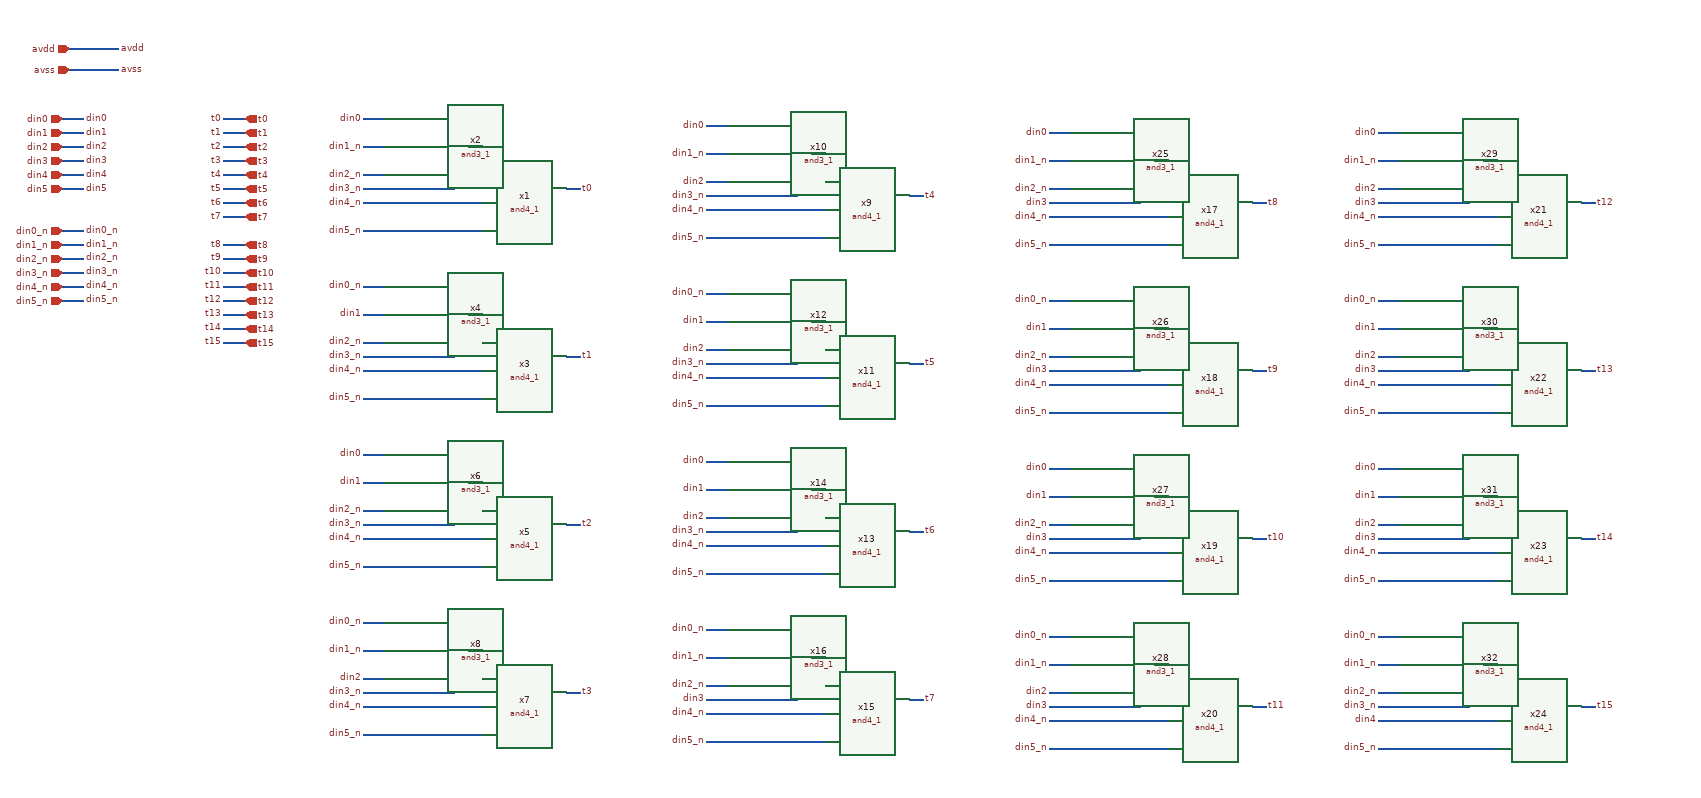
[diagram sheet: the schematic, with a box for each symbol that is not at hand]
v {xschem version=3.4.5 file_version=1.2
}
G {}
K {}
V {}
S {}
E {}
N -50 -70 -20 -70 {
lab=din0}
N -50 -50 -20 -50 {
lab=din1}
N -50 -30 -20 -30 {
lab=din2}
N -50 -10 -20 -10 {
lab=din3}
N -50 10 -20 10 {
lab=din4}
N -50 30 -20 30 {
lab=din5}
N -50 90 -20 90 {
lab=din0_n}
N -50 110 -20 110 {
lab=din1_n}
N -50 130 -20 130 {
lab=din2_n}
N -50 150 -20 150 {
lab=din3_n}
N -50 170 -20 170 {
lab=din4_n}
N -50 190 -20 190 {
lab=din5_n}
N 180 -70 210 -70 {
lab=t0}
N 180 -50 210 -50 {
lab=t1}
N 180 -30 210 -30 {
lab=t2}
N 180 -10 210 -10 {
lab=t3}
N 180 10 210 10 {
lab=t4}
N 180 30 210 30 {
lab=t5}
N 180 50 210 50 {
lab=t6}
N 180 70 210 70 {
lab=t7}
N 180 110 210 110 {
lab=t8}
N 180 130 210 130 {
lab=t9}
N 180 150 210 150 {
lab=t10}
N 180 170 210 170 {
lab=t11}
N 180 190 210 190 {
lab=t12}
N 180 210 210 210 {
lab=t13}
N 180 230 210 230 {
lab=t14}
N 180 250 210 250 {
lab=t15}
N 530 -30 550 -30 {
lab=#net1}
N 380 -70 410 -70 {
lab=din0_n}
N 380 -30 410 -30 {
lab=din1_n}
N 380 10 410 10 {
lab=din2_n}
N 510 10 550 10 {
lab=din3_n}
N 510 10 510 30 {
lab=din3_n}
N 380 30 510 30 {
lab=din3_n}
N 380 50 550 50 {
lab=din4_n}
N 380 90 550 90 {
lab=din5_n}
N 670 30 690 30 {
lab=t0}
N 530 210 550 210 {
lab=#net1}
N 380 170 410 170 {
lab=din0_n}
N 380 210 410 210 {
lab=din1_n}
N 380 250 410 250 {
lab=din2_n}
N 510 250 550 250 {
lab=din3_n}
N 510 250 510 270 {
lab=din3_n}
N 380 270 510 270 {
lab=din3_n}
N 380 290 550 290 {
lab=din4_n}
N 380 330 550 330 {
lab=din5_n}
N 670 270 690 270 {
lab=t0}
N 530 450 550 450 {
lab=#net1}
N 380 410 410 410 {
lab=din0_n}
N 380 450 410 450 {
lab=din1_n}
N 380 490 410 490 {
lab=din2_n}
N 510 490 550 490 {
lab=din3_n}
N 510 490 510 510 {
lab=din3_n}
N 380 510 510 510 {
lab=din3_n}
N 380 530 550 530 {
lab=din4_n}
N 380 570 550 570 {
lab=din5_n}
N 670 510 690 510 {
lab=t0}
N 530 690 550 690 {
lab=#net1}
N 380 650 410 650 {
lab=din0_n}
N 380 690 410 690 {
lab=din1_n}
N 380 730 410 730 {
lab=din2_n}
N 510 730 550 730 {
lab=din3_n}
N 510 730 510 750 {
lab=din3_n}
N 380 750 510 750 {
lab=din3_n}
N 380 770 550 770 {
lab=din4_n}
N 380 810 550 810 {
lab=din5_n}
N 670 750 690 750 {
lab=t0}
N 1020 -20 1040 -20 {
lab=#net1}
N 870 -60 900 -60 {
lab=din0_n}
N 870 -20 900 -20 {
lab=din1_n}
N 870 20 900 20 {
lab=din2_n}
N 1000 20 1040 20 {
lab=din3_n}
N 1000 20 1000 40 {
lab=din3_n}
N 870 40 1000 40 {
lab=din3_n}
N 870 60 1040 60 {
lab=din4_n}
N 870 100 1040 100 {
lab=din5_n}
N 1160 40 1180 40 {
lab=t0}
N 1020 220 1040 220 {
lab=#net1}
N 870 180 900 180 {
lab=din0_n}
N 870 220 900 220 {
lab=din1_n}
N 870 260 900 260 {
lab=din2_n}
N 1000 260 1040 260 {
lab=din3_n}
N 1000 260 1000 280 {
lab=din3_n}
N 870 280 1000 280 {
lab=din3_n}
N 870 300 1040 300 {
lab=din4_n}
N 870 340 1040 340 {
lab=din5_n}
N 1160 280 1180 280 {
lab=t0}
N 1020 460 1040 460 {
lab=#net1}
N 870 420 900 420 {
lab=din0_n}
N 870 460 900 460 {
lab=din1_n}
N 870 500 900 500 {
lab=din2_n}
N 1000 500 1040 500 {
lab=din3_n}
N 1000 500 1000 520 {
lab=din3_n}
N 870 520 1000 520 {
lab=din3_n}
N 870 540 1040 540 {
lab=din4_n}
N 870 580 1040 580 {
lab=din5_n}
N 1160 520 1180 520 {
lab=t0}
N 1020 700 1040 700 {
lab=#net1}
N 870 660 900 660 {
lab=din0_n}
N 870 700 900 700 {
lab=din1_n}
N 870 740 900 740 {
lab=din2_n}
N 1000 740 1040 740 {
lab=din3_n}
N 1000 740 1000 760 {
lab=din3_n}
N 870 760 1000 760 {
lab=din3_n}
N 870 780 1040 780 {
lab=din4_n}
N 870 820 1040 820 {
lab=din5_n}
N 1160 760 1180 760 {
lab=t0}
N 1510 -10 1530 -10 {
lab=#net1}
N 1360 -50 1390 -50 {
lab=din0_n}
N 1360 -10 1390 -10 {
lab=din1_n}
N 1360 30 1390 30 {
lab=din2_n}
N 1490 30 1530 30 {
lab=din3_n}
N 1490 30 1490 50 {
lab=din3_n}
N 1360 50 1490 50 {
lab=din3_n}
N 1360 70 1530 70 {
lab=din4_n}
N 1360 110 1530 110 {
lab=din5_n}
N 1650 50 1670 50 {
lab=t0}
N 1510 230 1530 230 {
lab=#net1}
N 1360 190 1390 190 {
lab=din0_n}
N 1360 230 1390 230 {
lab=din1_n}
N 1360 270 1390 270 {
lab=din2_n}
N 1490 270 1530 270 {
lab=din3_n}
N 1490 270 1490 290 {
lab=din3_n}
N 1360 290 1490 290 {
lab=din3_n}
N 1360 310 1530 310 {
lab=din4_n}
N 1360 350 1530 350 {
lab=din5_n}
N 1650 290 1670 290 {
lab=t0}
N 1510 470 1530 470 {
lab=#net1}
N 1360 430 1390 430 {
lab=din0_n}
N 1360 470 1390 470 {
lab=din1_n}
N 1360 510 1390 510 {
lab=din2_n}
N 1490 510 1530 510 {
lab=din3_n}
N 1490 510 1490 530 {
lab=din3_n}
N 1360 530 1490 530 {
lab=din3_n}
N 1360 550 1530 550 {
lab=din4_n}
N 1360 590 1530 590 {
lab=din5_n}
N 1650 530 1670 530 {
lab=t0}
N 1510 710 1530 710 {
lab=#net1}
N 1360 670 1390 670 {
lab=din0_n}
N 1360 710 1390 710 {
lab=din1_n}
N 1360 750 1390 750 {
lab=din2_n}
N 1490 750 1530 750 {
lab=din3_n}
N 1490 750 1490 770 {
lab=din3_n}
N 1360 770 1490 770 {
lab=din3_n}
N 1360 790 1530 790 {
lab=din4_n}
N 1360 830 1530 830 {
lab=din5_n}
N 1650 770 1670 770 {
lab=t0}
N 1980 -10 2000 -10 {
lab=#net1}
N 1830 -50 1860 -50 {
lab=din0_n}
N 1830 -10 1860 -10 {
lab=din1_n}
N 1830 30 1860 30 {
lab=din2_n}
N 1960 30 2000 30 {
lab=din3_n}
N 1960 30 1960 50 {
lab=din3_n}
N 1830 50 1960 50 {
lab=din3_n}
N 1830 70 2000 70 {
lab=din4_n}
N 1830 110 2000 110 {
lab=din5_n}
N 2120 50 2140 50 {
lab=t0}
N 1980 230 2000 230 {
lab=#net1}
N 1830 190 1860 190 {
lab=din0_n}
N 1830 230 1860 230 {
lab=din1_n}
N 1830 270 1860 270 {
lab=din2_n}
N 1960 270 2000 270 {
lab=din3_n}
N 1960 270 1960 290 {
lab=din3_n}
N 1830 290 1960 290 {
lab=din3_n}
N 1830 310 2000 310 {
lab=din4_n}
N 1830 350 2000 350 {
lab=din5_n}
N 2120 290 2140 290 {
lab=t0}
N 1980 470 2000 470 {
lab=#net1}
N 1830 430 1860 430 {
lab=din0_n}
N 1830 470 1860 470 {
lab=din1_n}
N 1830 510 1860 510 {
lab=din2_n}
N 1960 510 2000 510 {
lab=din3_n}
N 1960 510 1960 530 {
lab=din3_n}
N 1830 530 1960 530 {
lab=din3_n}
N 1830 550 2000 550 {
lab=din4_n}
N 1830 590 2000 590 {
lab=din5_n}
N 2120 530 2140 530 {
lab=t0}
N 1980 710 2000 710 {
lab=#net1}
N 1830 670 1860 670 {
lab=din0_n}
N 1830 710 1860 710 {
lab=din1_n}
N 1830 750 1860 750 {
lab=din2_n}
N 1960 750 2000 750 {
lab=din3_n}
N 1960 750 1960 770 {
lab=din3_n}
N 1830 770 1960 770 {
lab=din3_n}
N 1830 790 2000 790 {
lab=din4_n}
N 1830 830 2000 830 {
lab=din5_n}
N 2120 770 2140 770 {
lab=t0}
N -40 -170 30 -170 {}
N -40 -140 30 -140 {}
C {devices/ipin.sym} -50 -70 0 0 {name=p1 lab=din0}
C {devices/ipin.sym} -50 -50 0 0 {name=p2 lab=din1}
C {devices/ipin.sym} -50 -30 0 0 {name=p3 lab=din2}
C {devices/ipin.sym} -50 -10 0 0 {name=p4 lab=din3}
C {devices/ipin.sym} -50 10 0 0 {name=p5 lab=din4}
C {devices/ipin.sym} -50 30 0 0 {name=p6 lab=din5}
C {devices/ipin.sym} -50 90 0 0 {name=p7 lab=din0_n}
C {devices/ipin.sym} -50 110 0 0 {name=p8 lab=din1_n}
C {devices/ipin.sym} -50 130 0 0 {name=p9 lab=din2_n}
C {devices/ipin.sym} -50 150 0 0 {name=p10 lab=din3_n}
C {devices/ipin.sym} -50 170 0 0 {name=p11 lab=din4_n}
C {devices/ipin.sym} -50 190 0 0 {name=p12 lab=din5_n}
C {devices/opin.sym} 210 -70 0 0 {name=p13 lab=t0}
C {devices/opin.sym} 210 -50 0 0 {name=p14 lab=t1}
C {devices/opin.sym} 210 -30 0 0 {name=p15 lab=t2}
C {devices/opin.sym} 210 -10 0 0 {name=p16 lab=t3}
C {devices/opin.sym} 210 10 0 0 {name=p17 lab=t4}
C {devices/opin.sym} 210 30 0 0 {name=p18 lab=t5}
C {devices/opin.sym} 210 50 0 0 {name=p19 lab=t6}
C {devices/opin.sym} 210 70 0 0 {name=p20 lab=t7}
C {devices/lab_pin.sym} 180 -70 0 0 {name=p21 sig_type=std_logic lab=t0}
C {devices/lab_pin.sym} 180 -50 0 0 {name=p22 sig_type=std_logic lab=t1}
C {devices/lab_pin.sym} 180 -30 0 0 {name=p23 sig_type=std_logic lab=t2}
C {devices/lab_pin.sym} 180 -10 0 0 {name=p24 sig_type=std_logic lab=t3}
C {devices/lab_pin.sym} 180 10 0 0 {name=p25 sig_type=std_logic lab=t4}
C {devices/lab_pin.sym} 180 30 0 0 {name=p26 sig_type=std_logic lab=t5}
C {devices/lab_pin.sym} 180 50 0 0 {name=p27 sig_type=std_logic lab=t6}
C {devices/lab_pin.sym} 180 70 0 0 {name=p28 sig_type=std_logic lab=t7}
C {devices/lab_pin.sym} -20 -70 0 1 {name=p29 sig_type=std_logic lab=din0}
C {devices/lab_pin.sym} -20 -50 0 1 {name=p30 sig_type=std_logic lab=din1}
C {devices/lab_pin.sym} -20 -30 0 1 {name=p31 sig_type=std_logic lab=din2}
C {devices/lab_pin.sym} -20 -10 0 1 {name=p32 sig_type=std_logic lab=din3}
C {devices/lab_pin.sym} -20 10 0 1 {name=p33 sig_type=std_logic lab=din4}
C {devices/lab_pin.sym} -20 30 0 1 {name=p34 sig_type=std_logic lab=din5}
C {devices/lab_pin.sym} -20 90 0 1 {name=p35 sig_type=std_logic lab=din0_n}
C {devices/lab_pin.sym} -20 110 0 1 {name=p36 sig_type=std_logic lab=din1_n}
C {devices/lab_pin.sym} -20 130 0 1 {name=p37 sig_type=std_logic lab=din2_n}
C {devices/lab_pin.sym} -20 150 0 1 {name=p38 sig_type=std_logic lab=din3_n}
C {devices/lab_pin.sym} -20 170 0 1 {name=p39 sig_type=std_logic lab=din4_n}
C {devices/lab_pin.sym} -20 190 0 1 {name=p40 sig_type=std_logic lab=din5_n}
C {devices/opin.sym} 210 110 0 0 {name=p41 lab=t8}
C {devices/opin.sym} 210 130 0 0 {name=p42 lab=t9}
C {devices/opin.sym} 210 150 0 0 {name=p43 lab=t10}
C {devices/opin.sym} 210 170 0 0 {name=p44 lab=t11}
C {devices/opin.sym} 210 190 0 0 {name=p45 lab=t12}
C {devices/opin.sym} 210 210 0 0 {name=p46 lab=t13}
C {devices/opin.sym} 210 230 0 0 {name=p47 lab=t14}
C {devices/opin.sym} 210 250 0 0 {name=p48 lab=t15}
C {devices/lab_pin.sym} 180 110 0 0 {name=p49 sig_type=std_logic lab=t8}
C {devices/lab_pin.sym} 180 130 0 0 {name=p50 sig_type=std_logic lab=t9}
C {devices/lab_pin.sym} 180 150 0 0 {name=p51 sig_type=std_logic lab=t10}
C {devices/lab_pin.sym} 180 170 0 0 {name=p52 sig_type=std_logic lab=t11}
C {devices/lab_pin.sym} 180 190 0 0 {name=p53 sig_type=std_logic lab=t12}
C {devices/lab_pin.sym} 180 210 0 0 {name=p54 sig_type=std_logic lab=t13}
C {devices/lab_pin.sym} 180 230 0 0 {name=p55 sig_type=std_logic lab=t14}
C {devices/lab_pin.sym} 180 250 0 0 {name=p56 sig_type=std_logic lab=t15}
C {sky130_stdcells/and4_1.sym} 610 30 0 0 {name=x1 VGND=avss VNB=avss VPB=avdd VPWR=avdd prefix=sky130_fd_sc_hvl__ }
C {sky130_stdcells/and3_1.sym} 470 -30 0 0 {name=x2 VGND=avss VNB=avss VPB=avdd VPWR=avdd prefix=sky130_fd_sc_hvl__ }
C {devices/lab_pin.sym} 690 30 0 1 {name=p57 sig_type=std_logic lab=t0}
C {devices/lab_pin.sym} 380 -70 0 0 {name=p58 sig_type=std_logic lab=din0}
C {devices/lab_pin.sym} 380 -30 0 0 {name=p59 sig_type=std_logic lab=din1_n}
C {devices/lab_pin.sym} 380 10 0 0 {name=p60 sig_type=std_logic lab=din2_n}
C {devices/lab_pin.sym} 380 30 0 0 {name=p61 sig_type=std_logic lab=din3_n}
C {devices/lab_pin.sym} 380 50 0 0 {name=p62 sig_type=std_logic lab=din4_n}
C {devices/lab_pin.sym} 380 90 0 0 {name=p63 sig_type=std_logic lab=din5_n}
C {devices/lab_pin.sym} 690 270 0 1 {name=p64 sig_type=std_logic lab=t1}
C {devices/lab_pin.sym} 380 170 0 0 {name=p65 sig_type=std_logic lab=din0_n}
C {devices/lab_pin.sym} 380 210 0 0 {name=p66 sig_type=std_logic lab=din1}
C {devices/lab_pin.sym} 380 250 0 0 {name=p67 sig_type=std_logic lab=din2_n}
C {devices/lab_pin.sym} 380 270 0 0 {name=p68 sig_type=std_logic lab=din3_n}
C {devices/lab_pin.sym} 380 290 0 0 {name=p69 sig_type=std_logic lab=din4_n}
C {devices/lab_pin.sym} 380 330 0 0 {name=p70 sig_type=std_logic lab=din5_n}
C {devices/lab_pin.sym} 690 510 0 1 {name=p71 sig_type=std_logic lab=t2}
C {devices/lab_pin.sym} 380 410 0 0 {name=p72 sig_type=std_logic lab=din0}
C {devices/lab_pin.sym} 380 450 0 0 {name=p73 sig_type=std_logic lab=din1}
C {devices/lab_pin.sym} 380 490 0 0 {name=p74 sig_type=std_logic lab=din2_n}
C {devices/lab_pin.sym} 380 510 0 0 {name=p75 sig_type=std_logic lab=din3_n}
C {devices/lab_pin.sym} 380 530 0 0 {name=p76 sig_type=std_logic lab=din4_n}
C {devices/lab_pin.sym} 380 570 0 0 {name=p77 sig_type=std_logic lab=din5_n}
C {devices/lab_pin.sym} 690 750 0 1 {name=p78 sig_type=std_logic lab=t3}
C {devices/lab_pin.sym} 380 650 0 0 {name=p79 sig_type=std_logic lab=din0_n}
C {devices/lab_pin.sym} 380 690 0 0 {name=p80 sig_type=std_logic lab=din1_n}
C {devices/lab_pin.sym} 380 730 0 0 {name=p81 sig_type=std_logic lab=din2}
C {devices/lab_pin.sym} 380 750 0 0 {name=p82 sig_type=std_logic lab=din3_n}
C {devices/lab_pin.sym} 380 770 0 0 {name=p83 sig_type=std_logic lab=din4_n}
C {devices/lab_pin.sym} 380 810 0 0 {name=p84 sig_type=std_logic lab=din5_n}
C {devices/lab_pin.sym} 1180 40 0 1 {name=p85 sig_type=std_logic lab=t4}
C {devices/lab_pin.sym} 870 -60 0 0 {name=p86 sig_type=std_logic lab=din0}
C {devices/lab_pin.sym} 870 -20 0 0 {name=p87 sig_type=std_logic lab=din1_n}
C {devices/lab_pin.sym} 870 20 0 0 {name=p88 sig_type=std_logic lab=din2}
C {devices/lab_pin.sym} 870 40 0 0 {name=p89 sig_type=std_logic lab=din3_n}
C {devices/lab_pin.sym} 870 60 0 0 {name=p90 sig_type=std_logic lab=din4_n}
C {devices/lab_pin.sym} 870 100 0 0 {name=p91 sig_type=std_logic lab=din5_n}
C {devices/lab_pin.sym} 1180 280 0 1 {name=p92 sig_type=std_logic lab=t5}
C {devices/lab_pin.sym} 870 180 0 0 {name=p93 sig_type=std_logic lab=din0_n}
C {devices/lab_pin.sym} 870 220 0 0 {name=p94 sig_type=std_logic lab=din1}
C {devices/lab_pin.sym} 870 260 0 0 {name=p95 sig_type=std_logic lab=din2}
C {devices/lab_pin.sym} 870 280 0 0 {name=p96 sig_type=std_logic lab=din3_n}
C {devices/lab_pin.sym} 870 300 0 0 {name=p97 sig_type=std_logic lab=din4_n}
C {devices/lab_pin.sym} 870 340 0 0 {name=p98 sig_type=std_logic lab=din5_n}
C {devices/lab_pin.sym} 1180 520 0 1 {name=p99 sig_type=std_logic lab=t6}
C {devices/lab_pin.sym} 870 420 0 0 {name=p100 sig_type=std_logic lab=din0}
C {devices/lab_pin.sym} 870 460 0 0 {name=p101 sig_type=std_logic lab=din1}
C {devices/lab_pin.sym} 870 500 0 0 {name=p102 sig_type=std_logic lab=din2}
C {devices/lab_pin.sym} 870 520 0 0 {name=p103 sig_type=std_logic lab=din3_n}
C {devices/lab_pin.sym} 870 540 0 0 {name=p104 sig_type=std_logic lab=din4_n}
C {devices/lab_pin.sym} 870 580 0 0 {name=p105 sig_type=std_logic lab=din5_n}
C {devices/lab_pin.sym} 1180 760 0 1 {name=p106 sig_type=std_logic lab=t7}
C {devices/lab_pin.sym} 870 660 0 0 {name=p107 sig_type=std_logic lab=din0_n}
C {devices/lab_pin.sym} 870 700 0 0 {name=p108 sig_type=std_logic lab=din1_n}
C {devices/lab_pin.sym} 870 740 0 0 {name=p109 sig_type=std_logic lab=din2_n}
C {devices/lab_pin.sym} 870 760 0 0 {name=p110 sig_type=std_logic lab=din3}
C {devices/lab_pin.sym} 870 780 0 0 {name=p111 sig_type=std_logic lab=din4_n}
C {devices/lab_pin.sym} 870 820 0 0 {name=p112 sig_type=std_logic lab=din5_n}
C {devices/lab_pin.sym} 1670 50 0 1 {name=p113 sig_type=std_logic lab=t8}
C {devices/lab_pin.sym} 1360 -50 0 0 {name=p114 sig_type=std_logic lab=din0}
C {devices/lab_pin.sym} 1360 -10 0 0 {name=p115 sig_type=std_logic lab=din1_n}
C {devices/lab_pin.sym} 1360 30 0 0 {name=p116 sig_type=std_logic lab=din2_n}
C {devices/lab_pin.sym} 1360 50 0 0 {name=p117 sig_type=std_logic lab=din3}
C {devices/lab_pin.sym} 1360 70 0 0 {name=p118 sig_type=std_logic lab=din4_n}
C {devices/lab_pin.sym} 1360 110 0 0 {name=p119 sig_type=std_logic lab=din5_n}
C {devices/lab_pin.sym} 1670 290 0 1 {name=p120 sig_type=std_logic lab=t9}
C {devices/lab_pin.sym} 1360 190 0 0 {name=p121 sig_type=std_logic lab=din0_n}
C {devices/lab_pin.sym} 1360 230 0 0 {name=p122 sig_type=std_logic lab=din1}
C {devices/lab_pin.sym} 1360 270 0 0 {name=p123 sig_type=std_logic lab=din2_n}
C {devices/lab_pin.sym} 1360 290 0 0 {name=p124 sig_type=std_logic lab=din3}
C {devices/lab_pin.sym} 1360 310 0 0 {name=p125 sig_type=std_logic lab=din4_n}
C {devices/lab_pin.sym} 1360 350 0 0 {name=p126 sig_type=std_logic lab=din5_n}
C {devices/lab_pin.sym} 1670 530 0 1 {name=p127 sig_type=std_logic lab=t10}
C {devices/lab_pin.sym} 1360 430 0 0 {name=p128 sig_type=std_logic lab=din0}
C {devices/lab_pin.sym} 1360 470 0 0 {name=p129 sig_type=std_logic lab=din1}
C {devices/lab_pin.sym} 1360 510 0 0 {name=p130 sig_type=std_logic lab=din2_n}
C {devices/lab_pin.sym} 1360 530 0 0 {name=p131 sig_type=std_logic lab=din3}
C {devices/lab_pin.sym} 1360 550 0 0 {name=p132 sig_type=std_logic lab=din4_n}
C {devices/lab_pin.sym} 1360 590 0 0 {name=p133 sig_type=std_logic lab=din5_n}
C {devices/lab_pin.sym} 1670 770 0 1 {name=p134 sig_type=std_logic lab=t11}
C {devices/lab_pin.sym} 1360 670 0 0 {name=p135 sig_type=std_logic lab=din0_n}
C {devices/lab_pin.sym} 1360 710 0 0 {name=p136 sig_type=std_logic lab=din1_n}
C {devices/lab_pin.sym} 1360 750 0 0 {name=p137 sig_type=std_logic lab=din2}
C {devices/lab_pin.sym} 1360 770 0 0 {name=p138 sig_type=std_logic lab=din3}
C {devices/lab_pin.sym} 1360 790 0 0 {name=p139 sig_type=std_logic lab=din4_n}
C {devices/lab_pin.sym} 1360 830 0 0 {name=p140 sig_type=std_logic lab=din5_n}
C {devices/lab_pin.sym} 2140 50 0 1 {name=p141 sig_type=std_logic lab=t12}
C {devices/lab_pin.sym} 1830 -50 0 0 {name=p142 sig_type=std_logic lab=din0}
C {devices/lab_pin.sym} 1830 -10 0 0 {name=p143 sig_type=std_logic lab=din1_n}
C {devices/lab_pin.sym} 1830 30 0 0 {name=p144 sig_type=std_logic lab=din2}
C {devices/lab_pin.sym} 1830 50 0 0 {name=p145 sig_type=std_logic lab=din3}
C {devices/lab_pin.sym} 1830 70 0 0 {name=p146 sig_type=std_logic lab=din4_n}
C {devices/lab_pin.sym} 1830 110 0 0 {name=p147 sig_type=std_logic lab=din5_n}
C {devices/lab_pin.sym} 2140 290 0 1 {name=p148 sig_type=std_logic lab=t13}
C {devices/lab_pin.sym} 1830 190 0 0 {name=p149 sig_type=std_logic lab=din0_n}
C {devices/lab_pin.sym} 1830 230 0 0 {name=p150 sig_type=std_logic lab=din1}
C {devices/lab_pin.sym} 1830 270 0 0 {name=p151 sig_type=std_logic lab=din2}
C {devices/lab_pin.sym} 1830 290 0 0 {name=p152 sig_type=std_logic lab=din3}
C {devices/lab_pin.sym} 1830 310 0 0 {name=p153 sig_type=std_logic lab=din4_n}
C {devices/lab_pin.sym} 1830 350 0 0 {name=p154 sig_type=std_logic lab=din5_n}
C {devices/lab_pin.sym} 2140 530 0 1 {name=p155 sig_type=std_logic lab=t14}
C {devices/lab_pin.sym} 1830 430 0 0 {name=p156 sig_type=std_logic lab=din0}
C {devices/lab_pin.sym} 1830 470 0 0 {name=p157 sig_type=std_logic lab=din1}
C {devices/lab_pin.sym} 1830 510 0 0 {name=p158 sig_type=std_logic lab=din2}
C {devices/lab_pin.sym} 1830 530 0 0 {name=p159 sig_type=std_logic lab=din3}
C {devices/lab_pin.sym} 1830 550 0 0 {name=p160 sig_type=std_logic lab=din4_n}
C {devices/lab_pin.sym} 1830 590 0 0 {name=p161 sig_type=std_logic lab=din5_n}
C {devices/lab_pin.sym} 2140 770 0 1 {name=p162 sig_type=std_logic lab=t15}
C {devices/lab_pin.sym} 1830 670 0 0 {name=p163 sig_type=std_logic lab=din0_n}
C {devices/lab_pin.sym} 1830 710 0 0 {name=p164 sig_type=std_logic lab=din1_n}
C {devices/lab_pin.sym} 1830 750 0 0 {name=p165 sig_type=std_logic lab=din2_n}
C {devices/lab_pin.sym} 1830 770 0 0 {name=p166 sig_type=std_logic lab=din3_n}
C {devices/lab_pin.sym} 1830 790 0 0 {name=p167 sig_type=std_logic lab=din4}
C {devices/lab_pin.sym} 1830 830 0 0 {name=p168 sig_type=std_logic lab=din5_n}
C {devices/ipin.sym} -40 -170 0 0 {name=p169 lab=avdd}
C {devices/ipin.sym} -40 -140 0 0 {name=p170 lab=avss}
C {devices/lab_pin.sym} 30 -170 0 1 {name=p171 sig_type=std_logic lab=avdd}
C {devices/lab_pin.sym} 30 -140 0 1 {name=p172 sig_type=std_logic lab=avss}
C {sky130_stdcells/and3_1.sym} 470 210 0 0 {name=x4 VGND=avss VNB=avss VPB=avdd VPWR=avdd prefix=sky130_fd_sc_hvl__ }
C {sky130_stdcells/and3_1.sym} 470 450 0 0 {name=x6 VGND=avss VNB=avss VPB=avdd VPWR=avdd prefix=sky130_fd_sc_hvl__ }
C {sky130_stdcells/and3_1.sym} 470 690 0 0 {name=x8 VGND=avss VNB=avss VPB=avdd VPWR=avdd prefix=sky130_fd_sc_hvl__ }
C {sky130_stdcells/and3_1.sym} 960 -20 0 0 {name=x10 VGND=avss VNB=avss VPB=avdd VPWR=avdd prefix=sky130_fd_sc_hvl__ }
C {sky130_stdcells/and3_1.sym} 960 220 0 0 {name=x12 VGND=avss VNB=avss VPB=avdd VPWR=avdd prefix=sky130_fd_sc_hvl__ }
C {sky130_stdcells/and3_1.sym} 960 460 0 0 {name=x14 VGND=avss VNB=avss VPB=avdd VPWR=avdd prefix=sky130_fd_sc_hvl__ }
C {sky130_stdcells/and3_1.sym} 960 700 0 0 {name=x16 VGND=avss VNB=avss VPB=avdd VPWR=avdd prefix=sky130_fd_sc_hvl__ }
C {sky130_stdcells/and4_1.sym} 610 270 0 0 {name=x3 VGND=avss VNB=avss VPB=avdd VPWR=avdd prefix=sky130_fd_sc_hvl__ }
C {sky130_stdcells/and4_1.sym} 610 510 0 0 {name=x5 VGND=avss VNB=avss VPB=avdd VPWR=avdd prefix=sky130_fd_sc_hvl__ }
C {sky130_stdcells/and4_1.sym} 610 750 0 0 {name=x7 VGND=avss VNB=avss VPB=avdd VPWR=avdd prefix=sky130_fd_sc_hvl__ }
C {sky130_stdcells/and4_1.sym} 1100 40 0 0 {name=x9 VGND=avss VNB=avss VPB=avdd VPWR=avdd prefix=sky130_fd_sc_hvl__ }
C {sky130_stdcells/and4_1.sym} 1100 280 0 0 {name=x11 VGND=avss VNB=avss VPB=avdd VPWR=avdd prefix=sky130_fd_sc_hvl__ }
C {sky130_stdcells/and4_1.sym} 1100 520 0 0 {name=x13 VGND=avss VNB=avss VPB=avdd VPWR=avdd prefix=sky130_fd_sc_hvl__ }
C {sky130_stdcells/and4_1.sym} 1100 760 0 0 {name=x15 VGND=avss VNB=avss VPB=avdd VPWR=avdd prefix=sky130_fd_sc_hvl__ }
C {sky130_stdcells/and4_1.sym} 1590 50 0 0 {name=x17 VGND=avss VNB=avss VPB=avdd VPWR=avdd prefix=sky130_fd_sc_hvl__ }
C {sky130_stdcells/and4_1.sym} 1590 290 0 0 {name=x18 VGND=avss VNB=avss VPB=avdd VPWR=avdd prefix=sky130_fd_sc_hvl__ }
C {sky130_stdcells/and4_1.sym} 1590 530 0 0 {name=x19 VGND=avss VNB=avss VPB=avdd VPWR=avdd prefix=sky130_fd_sc_hvl__ }
C {sky130_stdcells/and4_1.sym} 1590 770 0 0 {name=x20 VGND=avss VNB=avss VPB=avdd VPWR=avdd prefix=sky130_fd_sc_hvl__ }
C {sky130_stdcells/and4_1.sym} 2060 50 0 0 {name=x21 VGND=avss VNB=avss VPB=avdd VPWR=avdd prefix=sky130_fd_sc_hvl__ }
C {sky130_stdcells/and4_1.sym} 2060 290 0 0 {name=x22 VGND=avss VNB=avss VPB=avdd VPWR=avdd prefix=sky130_fd_sc_hvl__ }
C {sky130_stdcells/and4_1.sym} 2060 530 0 0 {name=x23 VGND=avss VNB=avss VPB=avdd VPWR=avdd prefix=sky130_fd_sc_hvl__ }
C {sky130_stdcells/and4_1.sym} 2060 770 0 0 {name=x24 VGND=avss VNB=avss VPB=avdd VPWR=avdd prefix=sky130_fd_sc_hvl__ }
C {sky130_stdcells/and3_1.sym} 1450 -10 0 0 {name=x25 VGND=avss VNB=avss VPB=avdd VPWR=avdd prefix=sky130_fd_sc_hvl__ }
C {sky130_stdcells/and3_1.sym} 1450 230 0 0 {name=x26 VGND=avss VNB=avss VPB=avdd VPWR=avdd prefix=sky130_fd_sc_hvl__ }
C {sky130_stdcells/and3_1.sym} 1450 470 0 0 {name=x27 VGND=avss VNB=avss VPB=avdd VPWR=avdd prefix=sky130_fd_sc_hvl__ }
C {sky130_stdcells/and3_1.sym} 1450 710 0 0 {name=x28 VGND=avss VNB=avss VPB=avdd VPWR=avdd prefix=sky130_fd_sc_hvl__ }
C {sky130_stdcells/and3_1.sym} 1920 -10 0 0 {name=x29 VGND=avss VNB=avss VPB=avdd VPWR=avdd prefix=sky130_fd_sc_hvl__ }
C {sky130_stdcells/and3_1.sym} 1920 230 0 0 {name=x30 VGND=avss VNB=avss VPB=avdd VPWR=avdd prefix=sky130_fd_sc_hvl__ }
C {sky130_stdcells/and3_1.sym} 1920 470 0 0 {name=x31 VGND=avss VNB=avss VPB=avdd VPWR=avdd prefix=sky130_fd_sc_hvl__ }
C {sky130_stdcells/and3_1.sym} 1920 710 0 0 {name=x32 VGND=avss VNB=avss VPB=avdd VPWR=avdd prefix=sky130_fd_sc_hvl__ }
